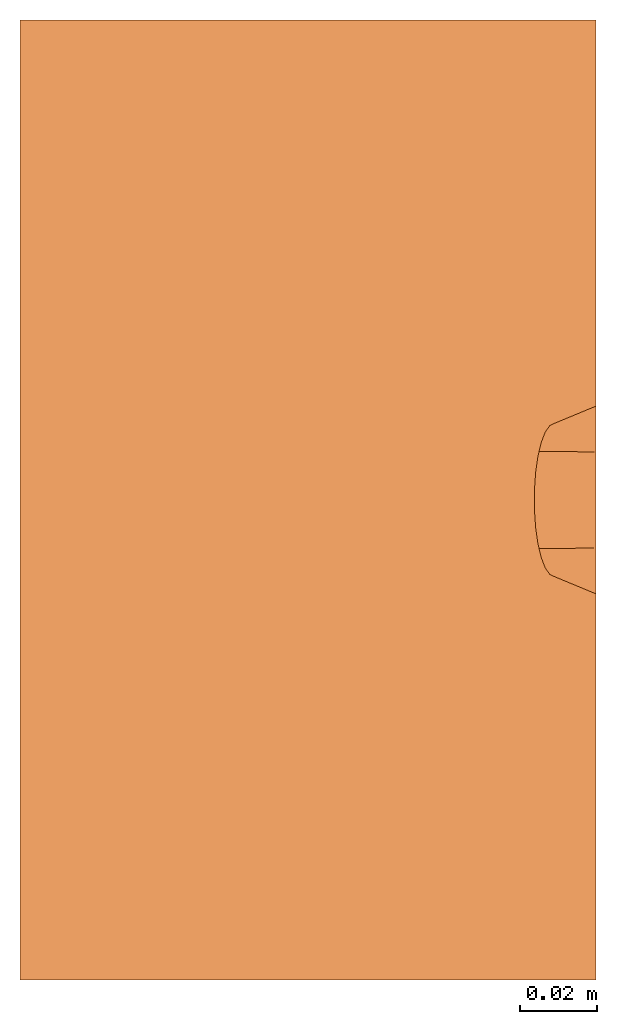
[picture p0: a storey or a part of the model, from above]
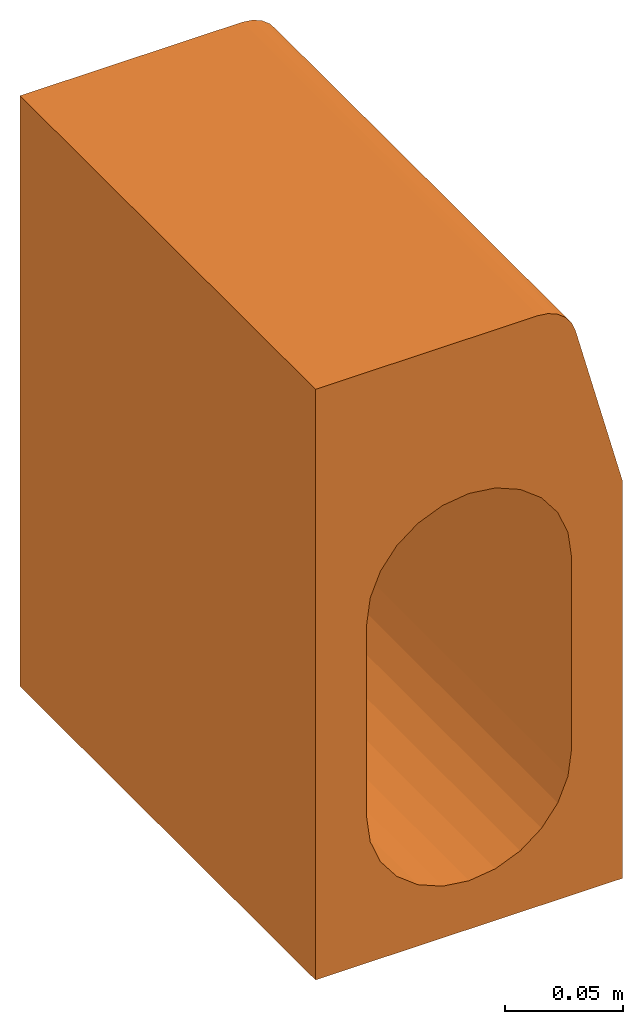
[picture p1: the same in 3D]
Properties of the parts of a building model (IFC2X3)

# File
Description: ViewDefinition [CoordinationView]
File name: 7960 - KDHB305 Channel - 250mm LG.ifc
Time: 2013-09-12T12:40:28
Written by: Autodesk Revit 2013
Made in: 20120221_2030(x64)

# IfcProject, Project Number
LongName: Project Name; Phase: Project Status

# IfcSite, Default
RefLatitude: 42, 21, 30, 344238; RefLongitude: -71, -3, -35, -194702; RefElevation: 0 mm

# IfcBuilding
Pset_BuildingCommon - NumberOfStoreys: 2
Other - Client Name: Owner; Project Status: Project Status; Project Number: Project Number; Project Address: Enter address here; Project Name: Project Name; Project Issue Date: Issue Date

# IfcBuildingStorey (2)
Constraints - Elevation Base: 0
Graphics - Symbol at End 2 Default: yes; Color: 0; Line Pattern: Center; Line Weight: 1; Symbol: M_Level Head - Circle: M_Level Head - Circle; Symbol at End 1 Default: no
Identity Data - Structural: no; Building Story: yes
Dimensions - Computation Height: 0 mm
Name | LongName = Name | Elevation (mm) = Constraints, Elevation (mm)
T.O. Fnd. Wall | T.O. Fnd. Wall | -300
Level 1 | Level 1 | 0

# IfcBuildingElementProxy: 7960 - KDHB305 Channel - 250mm LG, Civil-Drainage-Channel-ACO-KerbDrain-HB305 - PART 1:7960 - KDHB305 Channel - 250mm LG:7960 - KDHB305 Channel - 250mm LG:255899
In: T.O. Fnd. Wall
Material: ACO Polymer Concrete.
Other - Revision: 1
Dimensions - Staright Void Depth: -180 mm; Void_Width: 150 mm; I/O Endcap Void depth: 6000 mm; Void_Length: 250 mm; Volume: 6456865 mm3
Green Building Properties - Access Cover/Frame Recycled Material Content: N/A; Channel Recycled Material Content: 20% minimum; End Cap Recyclable: N/A; Access Cover/Frame Recyclable: N/A; End Cap Recycled Material Content: N/A; Channel Recyclable: Fully recyclable
Phasing - Phase Created: Phase 1
Constraints - Moves With Nearby Elements: no; Level: Level: Level 1
Pset_BuildingElementProxyCommon - Reference: 7960 - KDHB305 Channel - 250mm LG
Identity Data - Assembly Description: Rain Water Drainage; Installation guidelines: http://www.aco.co.uk/download.php?id=120; OmniClass Title: Rainwater Removal; Maintenance guidelines: http://www.aco.co.uk/download.php?id=120; Fax: +44 (0)1462 815895; Type Comments: ACO KerbDrain HB305 half battered kerb unit 250mm long; Manufacturer: ACO Technologies plc - ACO Water Management Division; OmniClass Number: 23.70.50.24; Telephone: +44 (0)1462 816666; Product Code: 7960; Assembly Code: D2040; Product Page URL: http://www.aco.co.uk/product_detail.php?id=3; E-mail Sales: customersupport@aco.co.uk; Model: ACO KerbDrain HB305; Cost: 0; Product brochure: http://www.aco.co.uk/download.php?id=120; URL: www.aco.co.uk; Price: POA - contact ACO; E-mail Technical: technical@aco.co.uk; Address: ACO Business Park, Hitchin Road, Shefford, Bedfordshire, United Kingdom SG17 5TE; Model Description: Combined kerb and drainage system
Data - Concrete Surround Volume - Load Class A 15 - D 400 - Concrete Pavement: 0.14m³/m; Invert Depth: 280mm; Installation - Concrete Grade: Refer to brochure; Product Dimensions: 250mm x 150mm x 305mm (LxWxH); Concrete Surround Volume - Load Class A 15 - D 400 - Grass or Asphalt Pavement: 0.13m³/m; Hydraulic Performance: http://www.aco.co.uk/download.php?id=120; Connection Pipe O.D: N/A; Load Class: A 15 - D 400; Drainage Slot Width: 50mm; ACO Hydraulic Design Software: http://www.acodesign.co.uk; Channel C.S.A: 0.02m²; Product Standard: BS EN 1433:2002, CE marked, Kitemarked; Product Weight: 12 Kg; Drainage Slot Intake area: 14592mm²/m
Construction - KDHB305 - Centre stone: no; KDHB305 - RH drop kerb: no; KDHB305 - Access Unit: no; KDHB305 - LH Inlet/Outlet end cap: no; KDHB305 - Flush LH dropkerb: no; KDHB305 - Drainable centre stone: no; KDHB305 - RH Inlet/outlet end cap: no; KDHB305 - Closing end cap: no; KDHB305 - Channel unit - 250mm: yes; KDHB305 - Channel unit - 500mm: no; KDHB305 - LH drop kerb: no; KDHB305 - Channel unit - 1000mm: no; KDHB305 - Flush RH dropkerb: no; I/O Pipe: no; KDHB305 - Blind unit: no; KDHB305 - Perforated centre stone: no
General - SerialNumber: 0.000000; TagNumber: 0.000000
Materials and Finishes - Channel Material: Vienite® Synthetic Resin Concrete; Connection Pipe Material: N/A; Channel Colour: Grey; End Cap Material: N/A; Connection Pipe Material Colour: N/A; Access Cover/Frame Material: N/A; End Cap Colour: N/A; Access Cover/Frame Colour: N/A; Access Cover/Frame Finish: N/A

# IfcOpeningElement: Recess (2)
In: Level 1
Dimensions - Thickness: 400 mm; Area: 53016081 mm2; Volume: 21199682206 mm3; Perimeter: 29157.2 mm
Constraints - Room Bounding: yes; Related to Mass: no; Height Offset From Level: 0 mm; Level: Level: Level 1
Structural - Structural: no; Enable Analytical Model: no
Phasing - Phase Created: Phase 1
Construction - Default Thickness: 400 mm; Function: 0
Analytical Properties - Roughness: 1; Absorptance: 0.1
Graphics - Coarse Scale Fill Color: 0

# IfcSlab: Floor:Generic Floor - 400mm, Floor:Generic Floor - 400mm:184025
In: Level 1
PredefinedType: FLOOR; Material: Default Floor 400 mm
Dimensions - Thickness: 400 mm; Area: 53016081 mm2; Volume: 21199682206 mm3; Perimeter: 29157.2 mm
Constraints - Room Bounding: yes; Related to Mass: no; Height Offset From Level: 0 mm; Level: Level: Level 1
Structural - Structural: no; Enable Analytical Model: no
Phasing - Phase Created: Phase 1
Pset_SlabCommon - Reference: Generic Floor - 400mm; IsExternal: no; LoadBearing: yes
Construction - Default Thickness: 400 mm; Function: 0
Analytical Properties - Roughness: 1; Absorptance: 0.1
Graphics - Coarse Scale Fill Color: 0
